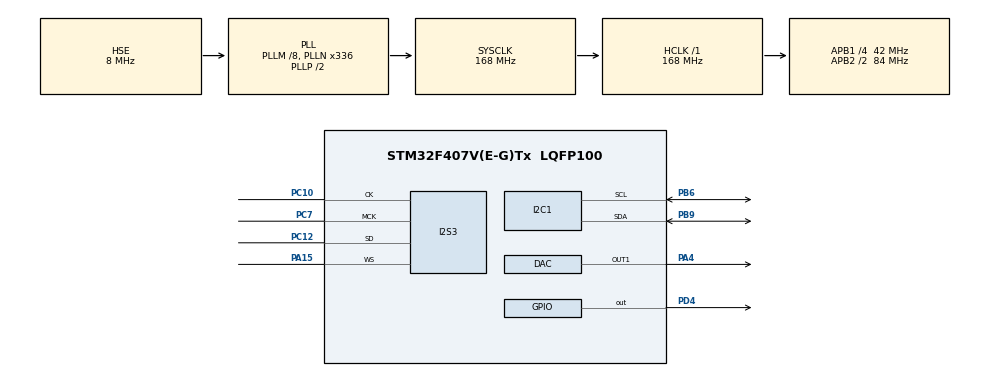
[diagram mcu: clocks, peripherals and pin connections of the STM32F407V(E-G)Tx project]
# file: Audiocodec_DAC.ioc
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Dma.Request0=SPI3_TX
Dma.SPI3_TX.0.Direction=DMA_MEMORY_TO_PERIPH
Dma.SPI3_TX.0.FIFOMode=DMA_FIFOMODE_ENABLE
Dma.SPI3_TX.0.FIFOThreshold=DMA_FIFO_THRESHOLD_FULL
Dma.SPI3_TX.0.Instance=DMA1_Stream5
Dma.SPI3_TX.0.MemBurst=DMA_MBURST_SINGLE
Dma.SPI3_TX.0.MemDataAlignment=DMA_MDATAALIGN_HALFWORD
Dma.SPI3_TX.0.MemInc=DMA_MINC_ENABLE
Dma.SPI3_TX.0.Mode=DMA_CIRCULAR
Dma.SPI3_TX.0.PeriphBurst=DMA_PBURST_SINGLE
Dma.SPI3_TX.0.PeriphDataAlignment=DMA_PDATAALIGN_HALFWORD
Dma.SPI3_TX.0.PeriphInc=DMA_PINC_DISABLE
Dma.SPI3_TX.0.Priority=DMA_PRIORITY_LOW
I2S3.AudioFreq=I2S_AUDIOFREQ_48K
I2S3.ErrorAudioFreq=-2.34 %
I2S3.FullDuplexMode=I2S_FULLDUPLEXMODE_DISABLE
I2S3.Instance=SPI$Index
I2S3.RealAudioFreq=46.875 KHz
I2S3.VirtualMode=I2S_MODE_MASTER
Mcu.Family=STM32F4
Mcu.Name=STM32F407V(E-G)Tx
Mcu.Package=LQFP100
NVIC.DMA1_Stream5_IRQn=true\:0\:0\:false\:false\:true\:false\:true
NVIC.PriorityGroup=NVIC_PRIORITYGROUP_0
NVIC.TIM2_IRQn=true\:0\:0\:false\:false\:true\:true\:true
NVIC.TIM8_TRG_COM_TIM14_IRQn=true\:0\:0\:false\:false\:true\:false\:true
NVIC.TimeBase=TIM8_TRG_COM_TIM14_IRQn
NVIC.TimeBaseIP=TIM14
PA15.Mode=Half_Duplex_Master
PA15.Signal=I2S3_WS
PA4.Signal=COMP_DAC1_group
PB6.Mode=I2C
PB6.Signal=I2C1_SCL
PB9.Mode=I2C
PB9.Signal=I2C1_SDA
PC10.Mode=Half_Duplex_Master
PC10.Signal=I2S3_CK
PC12.Mode=Half_Duplex_Master
PC12.Signal=I2S3_SD
PC14-OSC32_IN.Mode=LSE-External-Oscillator
PC14-OSC32_IN.Signal=RCC_OSC32_IN
PC15-OSC32_OUT.Mode=LSE-External-Oscillator
PC15-OSC32_OUT.Signal=RCC_OSC32_OUT
PC7.Mode=Master_Clock_Activated
PC7.Signal=I2S3_MCK
PD4.Signal=GPIO_Output
PH0-OSC_IN.Mode=HSE-External-Oscillator
PH0-OSC_IN.Signal=RCC_OSC_IN
PH1-OSC_OUT.Mode=HSE-External-Oscillator
PH1-OSC_OUT.Signal=RCC_OSC_OUT
ProjectManager.HeapSize=0x200
ProjectManager.StackSize=0x400
ProjectManager.TargetToolchain=STM32CubeIDE
RCC.48MHZClocksFreq_Value=48000000
RCC.AHBFreq_Value=168000000
RCC.APB1CLKDivider=RCC_HCLK_DIV4
RCC.APB1Freq_Value=42000000
RCC.APB1TimFreq_Value=84000000
RCC.APB2CLKDivider=RCC_HCLK_DIV2
RCC.APB2Freq_Value=84000000
RCC.APB2TimFreq_Value=168000000
RCC.CortexFreq_Value=168000000
RCC.HCLKFreq_Value=168000000
RCC.HSE_VALUE=8000000
RCC.HSI_VALUE=16000000
RCC.PLLM=8
RCC.PLLN=336
RCC.PLLQ=7
RCC.PLLSourceVirtual=RCC_PLLSOURCE_HSE
RCC.SYSCLKFreq_VALUE=168000000
RCC.SYSCLKSource=RCC_SYSCLKSOURCE_PLLCLK
RCC.VCOOutputFreq_Value=336000000
SH.COMP_DAC1_group.0=DAC_OUT1,DAC_OUT1
TIM2.Period=20-1
TIM2.Prescaler=84-1
TIM2.TIM_MasterOutputTrigger=TIM_TRGO_UPDATE
VP_SYS_VS_tim14.Mode=TIM14
VP_TIM2_VS_ClockSourceINT.Mode=Internal
board=STM32F407G-DISC1

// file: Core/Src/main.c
/* USER CODE BEGIN Header */
/**
  ******************************************************************************
  * @file           : main.c
  * @brief          : Main program body
  ******************************************************************************
  * @attention
  *
  * <h2><center>&copy; Copyright (c) 2023 STMicroelectronics.
  * All rights reserved.</center></h2>
  *
  * This software component is licensed by ST under BSD 3-Clause license,
  * the "License"; You may not use this file except in compliance with the
  * License. You may obtain a copy of the License at:
  *                        opensource.org/licenses/BSD-3-Clause
  *
  ******************************************************************************
  */
/* USER CODE END Header */
#include "main.h"
#include "stm32f4xx_hal.h"
/* USER CODE BEGIN Includes */
#include "MY_CS43L22.h"
#include <math.h>
/* USER CODE END Includes */

DAC_HandleTypeDef hdac;

I2C_HandleTypeDef hi2c1;

I2S_HandleTypeDef hi2s3;
DMA_HandleTypeDef hdma_spi3_tx;

TIM_HandleTypeDef htim2;

/* USER CODE BEGIN PV */
#define PI 3.14159f

#define F_SAMPLE 50000.0f
#define F_OUT 1000.0f
/* Coefficients for low-pass IIR filter */
float r_a0, r_a1, r_a2, r_b1, r_b2;
float rin_z1, rin_z2, rout_z1, rout_z2;

/* USER CODE END PV */

void SystemClock_Config(void);
static void MX_GPIO_Init(void);
static void MX_DAC_Init(void);
static void MX_I2C1_Init(void);
static void MX_I2S3_Init(void);
static void MX_DMA_Init(void);
static void MX_TIM2_Init(void);

/* USER CODE BEGIN 0 */
float mySinval;
float sample_dt ;
uint16_t sample_n;
uint16_t I_t;
uint32_t myDacValu;
int16_t dummy [4];
/* USER CODE END 0 */

int main(void)
{
    // Initialize filter coefficients (replace these with actual coefficients)

    r_a0 =  0.0365f;
    r_a1 = 0.07314f;
    r_a2 = 0.03657f;
    r_b1 = -1.3908f;
    r_b2 = 0.53719f;
  /* USER CODE BEGIN 1 */

sample_dt = F_OUT/F_SAMPLE;
sample_n = F_SAMPLE/F_OUT;

  /* USER CODE END 1 */

  /* MCU Configuration--------------------------------------------------------*/

  /* Reset of all peripherals, Initializes the Flash interface and the Systick. */
  HAL_Init();

  /* Configure the system clock */
  SystemClock_Config();

  /* Initialize all configured peripherals */
  MX_GPIO_Init();
  MX_DAC_Init();
  MX_I2C1_Init();
  MX_I2S3_Init();
  MX_DMA_Init();
  MX_TIM2_Init();
  /* USER CODE BEGIN 2 */

 CS43_Init(hi2c1,MODE_ANALOG_43);
 CS43_SetVolume(50);
 CS43_Enable_RightLeft(CS43_RIGHT_LEFT);
 CS43_Start();

HAL_I2S_Transmit_DMA(&hi2s3, (uint16_t*)dummy, 4);

HAL_DAC_Start(&hdac,DAC_CHANNEL_1);
HAL_TIM_Base_Start(&htim2);
  /* USER CODE END 2 */

  /* Infinite loop */
  while (1)
  {

  }
}

void SystemClock_Config(void)
{
  RCC_OscInitTypeDef RCC_OscInitStruct = {0};
  RCC_ClkInitTypeDef RCC_ClkInitStruct = {0};

  /** Configure the main internal regulator output voltage
  */
  __HAL_RCC_PWR_CLK_ENABLE();
  __HAL_PWR_VOLTAGESCALING_CONFIG(PWR_REGULATOR_VOLTAGE_SCALE1);
  /** Initializes the RCC Oscillators according to the specified parameters
  * in the RCC_OscInitTypeDef structure.
  */
  RCC_OscInitStruct.OscillatorType = RCC_OSCILLATORTYPE_HSE;
  RCC_OscInitStruct.HSEState = RCC_HSE_ON;
  RCC_OscInitStruct.PLL.PLLState = RCC_PLL_ON;
  RCC_OscInitStruct.PLL.PLLSource = RCC_PLLSOURCE_HSE;
  RCC_OscInitStruct.PLL.PLLM = 8;
  RCC_OscInitStruct.PLL.PLLN = 336;
  RCC_OscInitStruct.PLL.PLLP = RCC_PLLP_DIV2;
  RCC_OscInitStruct.PLL.PLLQ = 7;
  if (HAL_RCC_OscConfig(&RCC_OscInitStruct) != HAL_OK)
  {
    Error_Handler();
  }
  /** Initializes the CPU, AHB and APB buses clocks
  */
  RCC_ClkInitStruct.ClockType = RCC_CLOCKTYPE_HCLK|RCC_CLOCKTYPE_SYSCLK
                              |RCC_CLOCKTYPE_PCLK1|RCC_CLOCKTYPE_PCLK2;
  RCC_ClkInitStruct.SYSCLKSource = RCC_SYSCLKSOURCE_PLLCLK;
  RCC_ClkInitStruct.AHBCLKDivider = RCC_SYSCLK_DIV1;
  RCC_ClkInitStruct.APB1CLKDivider = RCC_HCLK_DIV4;
  RCC_ClkInitStruct.APB2CLKDivider = RCC_HCLK_DIV2;

  if (HAL_RCC_ClockConfig(&RCC_ClkInitStruct, FLASH_LATENCY_5) != HAL_OK)
  {
    Error_Handler();
  }
}

static void MX_DAC_Init(void)
{

  DAC_ChannelConfTypeDef sConfig = {0};

  /** DAC Initialization
  */
  hdac.Instance = DAC;
  if (HAL_DAC_Init(&hdac) != HAL_OK)
  {
    Error_Handler();
  }
  /** DAC channel OUT1 config
  */
  sConfig.DAC_Trigger = DAC_TRIGGER_NONE;
  sConfig.DAC_OutputBuffer = DAC_OUTPUTBUFFER_ENABLE;
  if (HAL_DAC_ConfigChannel(&hdac, &sConfig, DAC_CHANNEL_1) != HAL_OK)
  {
    Error_Handler();
  }

}

static void MX_I2C1_Init(void)
{

  hi2c1.Instance = I2C1;
  hi2c1.Init.ClockSpeed = 100000;
  hi2c1.Init.DutyCycle = I2C_DUTYCYCLE_2;
  hi2c1.Init.OwnAddress1 = 0;
  hi2c1.Init.AddressingMode = I2C_ADDRESSINGMODE_7BIT;
  hi2c1.Init.DualAddressMode = I2C_DUALADDRESS_DISABLE;
  hi2c1.Init.OwnAddress2 = 0;
  hi2c1.Init.GeneralCallMode = I2C_GENERALCALL_DISABLE;
  hi2c1.Init.NoStretchMode = I2C_NOSTRETCH_DISABLE;
  if (HAL_I2C_Init(&hi2c1) != HAL_OK)
  {
    Error_Handler();
  }

}

static void MX_I2S3_Init(void)
{

  hi2s3.Instance = SPI3;
  hi2s3.Init.Mode = I2S_MODE_MASTER_TX;
  hi2s3.Init.Standard = I2S_STANDARD_PHILIPS;
  hi2s3.Init.DataFormat = I2S_DATAFORMAT_16B;
  hi2s3.Init.MCLKOutput = I2S_MCLKOUTPUT_ENABLE;
  hi2s3.Init.AudioFreq = I2S_AUDIOFREQ_48K;
  hi2s3.Init.CPOL = I2S_CPOL_LOW;
  hi2s3.Init.ClockSource = I2S_CLOCK_PLL;
  hi2s3.Init.FullDuplexMode = I2S_FULLDUPLEXMODE_DISABLE;
  if (HAL_I2S_Init(&hi2s3) != HAL_OK)
  {
    Error_Handler();
  }

}

static void MX_TIM2_Init(void)
{

  TIM_ClockConfigTypeDef sClockSourceConfig = {0};
  TIM_MasterConfigTypeDef sMasterConfig = {0};

  htim2.Instance = TIM2;
  htim2.Init.Prescaler = 84-1;
  htim2.Init.CounterMode = TIM_COUNTERMODE_UP;
  htim2.Init.Period = 20-1;
  htim2.Init.ClockDivision = TIM_CLOCKDIVISION_DIV1;
  htim2.Init.AutoReloadPreload = TIM_AUTORELOAD_PRELOAD_DISABLE;
  if (HAL_TIM_Base_Init(&htim2) != HAL_OK)
  {
    Error_Handler();
  }
  sClockSourceConfig.ClockSource = TIM_CLOCKSOURCE_INTERNAL;
  if (HAL_TIM_ConfigClockSource(&htim2, &sClockSourceConfig) != HAL_OK)
  {
    Error_Handler();
  }
  sMasterConfig.MasterOutputTrigger = TIM_TRGO_UPDATE;
  sMasterConfig.MasterSlaveMode = TIM_MASTERSLAVEMODE_DISABLE;
  if (HAL_TIMEx_MasterConfigSynchronization(&htim2, &sMasterConfig) != HAL_OK)
  {
    Error_Handler();
  }

}

static void MX_DMA_Init(void)
{

  /* DMA controller clock enable */
  __HAL_RCC_DMA1_CLK_ENABLE();

  /* DMA interrupt init */
  /* DMA1_Stream5_IRQn interrupt configuration */
  HAL_NVIC_SetPriority(DMA1_Stream5_IRQn, 0, 0);
  HAL_NVIC_EnableIRQ(DMA1_Stream5_IRQn);

}

static void MX_GPIO_Init(void)
{
  GPIO_InitTypeDef GPIO_InitStruct = {0};

  /* GPIO Ports Clock Enable */
  __HAL_RCC_GPIOH_CLK_ENABLE();
  __HAL_RCC_GPIOA_CLK_ENABLE();
  __HAL_RCC_GPIOD_CLK_ENABLE();
  __HAL_RCC_GPIOC_CLK_ENABLE();
  __HAL_RCC_GPIOB_CLK_ENABLE();

  /*Configure GPIO pin Output Level */
  HAL_GPIO_WritePin(GPIOD, GPIO_PIN_12|GPIO_PIN_13|GPIO_PIN_14|GPIO_PIN_15, GPIO_PIN_RESET);

  /*Configure GPIO pin Output Level */
  HAL_GPIO_WritePin(GPIOB, GPIO_PIN_4, GPIO_PIN_RESET);

  /*Configure GPIO pins : PD12 PD13 PD14 PD15 */
  GPIO_InitStruct.Pin = GPIO_PIN_12|GPIO_PIN_13|GPIO_PIN_14|GPIO_PIN_15;
  GPIO_InitStruct.Mode = GPIO_MODE_OUTPUT_PP;
  GPIO_InitStruct.Pull = GPIO_NOPULL;
  GPIO_InitStruct.Speed = GPIO_SPEED_FREQ_LOW;
  HAL_GPIO_Init(GPIOD, &GPIO_InitStruct);

  /*Configure GPIO pin : PB4 */
  GPIO_InitStruct.Pin = GPIO_PIN_4;
  GPIO_InitStruct.Mode = GPIO_MODE_OUTPUT_PP;
  GPIO_InitStruct.Pull = GPIO_NOPULL;
  GPIO_InitStruct.Speed = GPIO_SPEED_FREQ_LOW;
  HAL_GPIO_Init(GPIOB, &GPIO_InitStruct);

}

/* USER CODE BEGIN 4 */
void HAL_TIM_PeriodElapsedCallback(TIM_HandleTypeDef *htim)
{
  /* Prevent unused argument(s) compilation warning */
  UNUSED(htim);

  /* NOTE : This function should not be modified, when the callback is needed,
            the HAL_TIM_PeriodElapsedCallback could be implemented in the user file
   */
  if(htim->Instance == TIM2)
  {
	mySinval = sinf(I_t * 2 * PI * sample_dt);
	myDacValu = (mySinval + 1) * 127 ;

    /* Apply low-pass IIR filter to the sine wave */
    float inSampleF = (float)myDacValu;
    float outSampleF =
        r_a0 * inSampleF +
        r_a1 * rin_z1 +
        r_a2 * rin_z2 +
        r_b1 * rout_z1 +
        r_b2 * rout_z2;

    rin_z2 = rin_z1;
    rin_z1 = inSampleF;
    rout_z2 = rout_z1;
    rout_z1 = outSampleF;

    /* Convert filtered sample to 12-bit DAC value */
    uint16_t filteredDacValue = (uint16_t)outSampleF;
	HAL_DAC_SetValue(&hdac, DAC1_CHANNEL_1,DAC_ALIGN_8B_R,filteredDacValue );

	I_t++;
	if(I_t >= sample_n) I_t=0 ;
  }

}

/* USER CODE END 4 */

void Error_Handler(void)
{
  __disable_irq();
  while (1)
  {
  }
}

/************************ (C) COPYRIGHT STMicroelectronics *****END OF FILE****/
